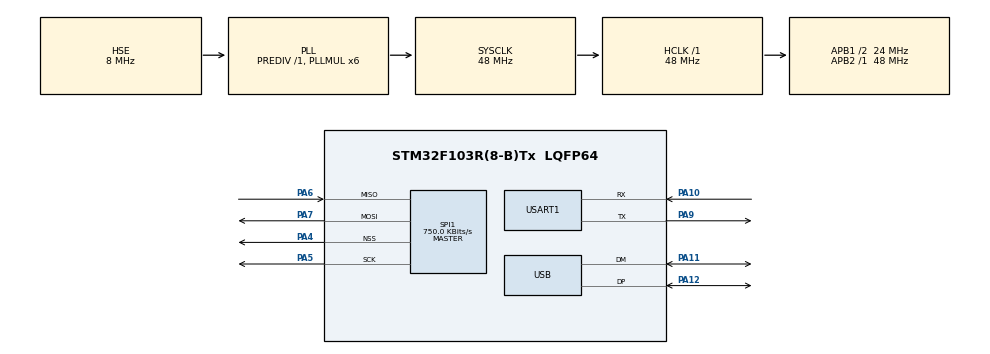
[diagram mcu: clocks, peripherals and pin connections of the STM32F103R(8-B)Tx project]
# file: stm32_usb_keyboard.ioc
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Mcu.Family=STM32F1
Mcu.Name=STM32F103R(8-B)Tx
Mcu.Package=LQFP64
NVIC.PriorityGroup=NVIC_PRIORITYGROUP_4
NVIC.USART1_IRQn=true\:0\:0\:false\:false\:true
NVIC.USB_LP_CAN1_RX0_IRQn=true\:0\:0\:false\:false\:true
PA10.Mode=Asynchronous
PA10.Signal=USART1_RX
PA11.Mode=Device
PA11.Signal=USB_DM
PA12.Mode=Device
PA12.Signal=USB_DP
PA4.Mode=NSS_Signal_Hard_Output
PA4.Signal=SPI1_NSS
PA5.Mode=Full_Duplex_Master
PA5.Signal=SPI1_SCK
PA6.Mode=Full_Duplex_Master
PA6.Signal=SPI1_MISO
PA7.Mode=Full_Duplex_Master
PA7.Signal=SPI1_MOSI
PA9.Mode=Asynchronous
PA9.Signal=USART1_TX
PC14-OSC32_IN.Mode=LSE-External-Oscillator
PC14-OSC32_IN.Signal=RCC_OSC32_IN
PC15-OSC32_OUT.Mode=LSE-External-Oscillator
PC15-OSC32_OUT.Signal=RCC_OSC32_OUT
PD0-OSC_IN.Mode=HSE-External-Oscillator
PD0-OSC_IN.Signal=RCC_OSC_IN
PD1-OSC_OUT.Mode=HSE-External-Oscillator
PD1-OSC_OUT.Signal=RCC_OSC_OUT
ProjectManager.HeapSize=0x200
ProjectManager.StackSize=0x400
ProjectManager.TargetToolchain=MDK-ARM V5
RCC.AHBFreq_Value=48000000
RCC.APB1CLKDivider=RCC_HCLK_DIV2
RCC.APB1Freq_Value=24000000
RCC.APB1TimFreq_Value=48000000
RCC.APB2Freq_Value=48000000
RCC.APB2TimFreq_Value=48000000
RCC.HCLKFreq_Value=48000000
RCC.HSIState=RCC_HSI_ON
RCC.PLLMUL=RCC_PLL_MUL6
RCC.SYSCLKFreq_VALUE=48000000
RCC.SYSCLKSource=RCC_SYSCLKSOURCE_PLLCLK
RCC.USBFreq_Value=48000000
SPI1.BaudRatePrescaler=SPI_BAUDRATEPRESCALER_64
SPI1.CalculateBaudRate=750.0 KBits/s
SPI1.Mode=SPI_MODE_MASTER
SPI1.VirtualNSS=VM_NSSHARD
USB_DEVICE.USBD_HandleTypeDef=hUsbDeviceFS
USB_DEVICE.VirtualMode=Hid
USB_DEVICE.VirtualModeFS=Hid_FS
VP_SYS_VS_ND.Mode=No_Debug
VP_USB_DEVICE_VS_USB_DEVICE_HID_FS.Mode=HID_FS
board=stm32_usb_keyboard

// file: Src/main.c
/**
  ******************************************************************************
  * File Name          : main.c
  * Description        : Main program body
  ******************************************************************************
  *
  * COPYRIGHT(c) 2018 STMicroelectronics
  *
  * Redistribution and use in source and binary forms, with or without modification,
  * are permitted provided that the following conditions are met:
  *   1. Redistributions of source code must retain the above copyright notice,
  *      this list of conditions and the following disclaimer.
  *   2. Redistributions in binary form must reproduce the above copyright notice,
  *      this list of conditions and the following disclaimer in the documentation
  *      and/or other materials provided with the distribution.
  *   3. Neither the name of STMicroelectronics nor the names of its contributors
  *      may be used to endorse or promote products derived from this software
  *      without specific prior written permission.
  *
  * THIS SOFTWARE IS PROVIDED BY THE COPYRIGHT HOLDERS AND CONTRIBUTORS "AS IS"
  * AND ANY EXPRESS OR IMPLIED WARRANTIES, INCLUDING, BUT NOT LIMITED TO, THE
  * IMPLIED WARRANTIES OF MERCHANTABILITY AND FITNESS FOR A PARTICULAR PURPOSE ARE
  * DISCLAIMED. IN NO EVENT SHALL THE COPYRIGHT HOLDER OR CONTRIBUTORS BE LIABLE
  * FOR ANY DIRECT, INDIRECT, INCIDENTAL, SPECIAL, EXEMPLARY, OR CONSEQUENTIAL
  * DAMAGES (INCLUDING, BUT NOT LIMITED TO, PROCUREMENT OF SUBSTITUTE GOODS OR
  * SERVICES; LOSS OF USE, DATA, OR PROFITS; OR BUSINESS INTERRUPTION) HOWEVER
  * CAUSED AND ON ANY THEORY OF LIABILITY, WHETHER IN CONTRACT, STRICT LIABILITY,
  * OR TORT (INCLUDING NEGLIGENCE OR OTHERWISE) ARISING IN ANY WAY OUT OF THE USE
  * OF THIS SOFTWARE, EVEN IF ADVISED OF THE POSSIBILITY OF SUCH DAMAGE.
  *
  ******************************************************************************
  */
#include "stm32f1xx_hal.h"
#include "usb_device.h"
#include "NRF24L01.h"

SPI_HandleTypeDef hspi1;

UART_HandleTypeDef huart1;

	uint8_t *nrf24L01tx_buf = NULL;
	uint8_t *nrf24L01rx_buf = NULL;
	uint8_t *rxdata = NULL;
/* USER CODE BEGIN PV */
/* Private variables ---------------------------------------------------------*/

/* USER CODE END PV */

void SystemClock_Config(void);
void Error_Handler(void);
static void MX_GPIO_Init(void);
static void MX_SPI1_Init(void);
static void MX_USART1_UART_Init(void);

/* USER CODE BEGIN PFP */
/* Private function prototypes -----------------------------------------------*/

/* USER CODE END PFP */

/* USER CODE BEGIN 0 */
extern USBD_HandleTypeDef hUsbDeviceFS;
/* USER CODE END 0 */

int main(void)
{

  /* USER CODE BEGIN 1 */
  uint8_t report[8];
	uint8_t i;
	uint8_t j;
	BYTE sta;

	uint8_t HID_Buffer[]={"Hello,HID!~"};
	nrf24L01tx_buf =  (uint8_t *)malloc(1*sizeof(uint8_t));
	*nrf24L01tx_buf = 0x0;
	nrf24L01rx_buf =  (uint8_t *)malloc(1*sizeof(uint8_t));
	*nrf24L01rx_buf = 0xff;
	rxdata = (uint8_t *)malloc(1*sizeof(uint8_t));
	*rxdata = 0x0;
	char buf[5];
	char count;
  /* USER CODE END 1 */

  /* MCU Configuration----------------------------------------------------------*/

  /* Reset of all peripherals, Initializes the Flash interface and the Systick. */
  HAL_Init();

  /* Configure the system clock */
  SystemClock_Config();

  /* Initialize all configured peripherals */
  MX_GPIO_Init();
  MX_SPI1_Init();
  MX_USB_DEVICE_Init();
  MX_USART1_UART_Init();
    NRF24L01B_Config();
  HAL_GPIO_WritePin(GPIOA, GPIO_PIN_3, GPIO_PIN_SET);
	SPI_RW_Reg(FLUSH_RX,0xff);
	SPI_RW_Reg(FLUSH_TX,0xff);

	HAL_NVIC_ClearPendingIRQ(EXTI1_IRQn);

	SetRX_Mode();
	HAL_GPIO_WritePin(GPIOA, GPIO_PIN_3, GPIO_PIN_SET);
	SPI_RW_Reg(NRF24L01_WRITEREG+STATUS,SPI_Read(STATUS));
  HAL_UART_Transmit(&huart1, HID_Buffer, 11, 10);
		for (i = 0;i < 0x7;i++)
		{
			report[i]	= 0;
		}
		report[2] = 0x53;
		for (i = 0;i < 0x7;i++)
		{

			report[i]	= 0;
		}
		SPI_Read_Buf(RX_ADDR_P0,buf,RX_ADR_WIDTH);

		for(count=0;count<RX_ADR_WIDTH;count++)
		{
				  HAL_UART_Transmit(&huart1,&buf[count], 1, 10);

		}
  /* Infinite loop */
  /* USER CODE BEGIN WHILE */
  while (1)
  {
		//report[0] = 0x01;
/*
		for(i = 0x58;i < 0x61;i++)
		{
			j = 0xff;
			while(j--);
			report[4] = i;
			USBD_HID_SendReport(&hUsbDeviceFS, report,8);
		}
*/

		if(*nrf24L01rx_buf != 0xff)
		{
			report[4] = *nrf24L01rx_buf;
			USBD_HID_SendReport(&hUsbDeviceFS, report,8);
			HID_Buffer[0] =  *nrf24L01rx_buf - 0x28;
			  HAL_UART_Transmit(&huart1, HID_Buffer, 11, 10);

			*nrf24L01rx_buf = 0xff;
		}
			sta=SPI_Read(STATUS);
			  HAL_UART_Transmit(&huart1, &sta, 1, 10);

  /* USER CODE END WHILE */

  }

}

/** System Clock Configuration
*/
void SystemClock_Config(void)
{

  RCC_OscInitTypeDef RCC_OscInitStruct;
  RCC_ClkInitTypeDef RCC_ClkInitStruct;
  RCC_PeriphCLKInitTypeDef PeriphClkInit;

  RCC_OscInitStruct.OscillatorType = RCC_OSCILLATORTYPE_HSE;
  RCC_OscInitStruct.HSEState = RCC_HSE_ON;
  RCC_OscInitStruct.HSEPredivValue = RCC_HSE_PREDIV_DIV1;
  RCC_OscInitStruct.PLL.PLLState = RCC_PLL_ON;
  RCC_OscInitStruct.PLL.PLLSource = RCC_PLLSOURCE_HSE;
  RCC_OscInitStruct.PLL.PLLMUL = RCC_PLL_MUL6;
  if (HAL_RCC_OscConfig(&RCC_OscInitStruct) != HAL_OK)
  {
    Error_Handler();
  }

  RCC_ClkInitStruct.ClockType = RCC_CLOCKTYPE_HCLK|RCC_CLOCKTYPE_SYSCLK
                              |RCC_CLOCKTYPE_PCLK1|RCC_CLOCKTYPE_PCLK2;
  RCC_ClkInitStruct.SYSCLKSource = RCC_SYSCLKSOURCE_PLLCLK;
  RCC_ClkInitStruct.AHBCLKDivider = RCC_SYSCLK_DIV1;
  RCC_ClkInitStruct.APB1CLKDivider = RCC_HCLK_DIV2;
  RCC_ClkInitStruct.APB2CLKDivider = RCC_HCLK_DIV1;
  if (HAL_RCC_ClockConfig(&RCC_ClkInitStruct, FLASH_LATENCY_1) != HAL_OK)
  {
    Error_Handler();
  }

  PeriphClkInit.PeriphClockSelection = RCC_PERIPHCLK_USB;
  PeriphClkInit.UsbClockSelection = RCC_USBCLKSOURCE_PLL;
  if (HAL_RCCEx_PeriphCLKConfig(&PeriphClkInit) != HAL_OK)
  {
    Error_Handler();
  }

  HAL_SYSTICK_Config(HAL_RCC_GetHCLKFreq()/1000);

  HAL_SYSTICK_CLKSourceConfig(SYSTICK_CLKSOURCE_HCLK);

  /* SysTick_IRQn interrupt configuration */
  HAL_NVIC_SetPriority(SysTick_IRQn, 0, 0);
}

/* SPI1 init function */
static void MX_SPI1_Init(void)
{

		GPIO_InitTypeDef GPIO_InitStruct;
  __HAL_RCC_GPIOA_CLK_ENABLE();

  __HAL_RCC_SPI1_CLK_ENABLE();

  /*Configure GPIO pin : PA1 */
  GPIO_InitStruct.Pin = GPIO_PIN_5|GPIO_PIN_7 ;
  GPIO_InitStruct.Mode = GPIO_MODE_AF_PP;
  GPIO_InitStruct.Pull = GPIO_PULLUP;
  HAL_GPIO_Init(GPIOA, &GPIO_InitStruct);

  GPIO_InitStruct.Pin = GPIO_PIN_6;
  GPIO_InitStruct.Mode = GPIO_MODE_AF_INPUT;
  GPIO_InitStruct.Pull = GPIO_NOPULL;
  HAL_GPIO_Init(GPIOA, &GPIO_InitStruct);

    GPIO_InitStruct.Pin = GPIO_PIN_4;
  GPIO_InitStruct.Mode = GPIO_MODE_OUTPUT_PP;
  GPIO_InitStruct.Pull = GPIO_PULLUP;
  HAL_GPIO_Init(GPIOA, &GPIO_InitStruct);

  hspi1.Instance = SPI1;
  hspi1.Init.Mode = SPI_MODE_MASTER;
  hspi1.Init.Direction = SPI_DIRECTION_2LINES;
  hspi1.Init.DataSize = SPI_DATASIZE_8BIT;
  hspi1.Init.CLKPolarity = SPI_POLARITY_LOW;
  hspi1.Init.CLKPhase = SPI_PHASE_1EDGE;
  hspi1.Init.NSS = SPI_NSS_SOFT;
  hspi1.Init.BaudRatePrescaler = SPI_BAUDRATEPRESCALER_128;
  hspi1.Init.FirstBit = SPI_FIRSTBIT_MSB;
  hspi1.Init.TIMode = SPI_TIMODE_DISABLE;
  hspi1.Init.CRCCalculation = SPI_CRCCALCULATION_DISABLE;
  hspi1.Init.CRCPolynomial = 10;
  if (HAL_SPI_Init(&hspi1) != HAL_OK)
  {
    Error_Handler();
  }

}

/* USART1 init function */
static void MX_USART1_UART_Init(void)
{

	GPIO_InitTypeDef GPIO_InitStruct;
	__HAL_RCC_USART1_CLK_ENABLE();

  GPIO_InitStruct.Pin = GPIO_PIN_9;
  GPIO_InitStruct.Mode = GPIO_MODE_AF_PP;
  GPIO_InitStruct.Pull = GPIO_PULLUP;
  GPIO_InitStruct.Speed = GPIO_SPEED_FREQ_HIGH;
  HAL_GPIO_Init(GPIOA, &GPIO_InitStruct);

    GPIO_InitStruct.Pin = GPIO_PIN_10;
  GPIO_InitStruct.Mode = GPIO_MODE_AF_INPUT;
  GPIO_InitStruct.Pull = GPIO_PULLUP;
  GPIO_InitStruct.Speed = GPIO_SPEED_FREQ_HIGH;
  HAL_GPIO_Init(GPIOA, &GPIO_InitStruct);

  huart1.Instance = USART1;
  huart1.Init.BaudRate = 115200;
  huart1.Init.WordLength = UART_WORDLENGTH_8B;
  huart1.Init.StopBits = UART_STOPBITS_1;
  huart1.Init.Parity = UART_PARITY_NONE;
  huart1.Init.Mode = UART_MODE_TX_RX;
  huart1.Init.HwFlowCtl = UART_HWCONTROL_NONE;
  huart1.Init.OverSampling = UART_OVERSAMPLING_16;
  if (HAL_UART_Init(&huart1) != HAL_OK)
  {
    Error_Handler();
  }

}

/** Configure pins as
        * Analog
        * Input
        * Output
        * EVENT_OUT
        * EXTI
*/
static void MX_GPIO_Init(void)
{

  /* GPIO Ports Clock Enable */

  GPIO_InitTypeDef GPIO_InitStruct;

  /* GPIO Ports Clock Enable */
  __HAL_RCC_GPIOC_CLK_ENABLE();
  __HAL_RCC_GPIOD_CLK_ENABLE();
  __HAL_RCC_GPIOA_CLK_ENABLE();
  __HAL_RCC_GPIOB_CLK_ENABLE();

  /*Configure GPIO pin : PA1 */
  GPIO_InitStruct.Pin = GPIO_PIN_1;
  GPIO_InitStruct.Mode = GPIO_MODE_IT_FALLING;
  GPIO_InitStruct.Pull = GPIO_NOPULL;
  HAL_GPIO_Init(GPIOA, &GPIO_InitStruct);

  HAL_NVIC_ClearPendingIRQ(EXTI1_IRQn);
	HAL_NVIC_SetPriority(EXTI1_IRQn, 1 ,0);
	HAL_NVIC_EnableIRQ(EXTI1_IRQn);

	GPIO_InitStruct.Pin = GPIO_PIN_3;
  GPIO_InitStruct.Mode = GPIO_MODE_OUTPUT_PP;
  GPIO_InitStruct.Pull = GPIO_PULLUP;
  HAL_GPIO_Init(GPIOA, &GPIO_InitStruct);
}

/* USER CODE BEGIN 4 */
/* USER CODE BEGIN 4 */
void EXTI1_IRQHandler(void)
{
	unsigned char sta,flag=0x01;
	uint8_t HID_Buffer[]={"intr"};

	HAL_NVIC_ClearPendingIRQ(EXTI1_IRQn);
	SetRX_Mode();
	HAL_GPIO_WritePin(GPIOA, GPIO_PIN_3, GPIO_PIN_SET);
	//USBD_CUSTOM_HID_SendReport(&hUsbDeviceFS, HID_Buffer,65);

	HAL_UART_Transmit(&huart1, HID_Buffer, 4, 10);

	//GPIO_WriteBit(GPIOA,GPIO_Pin_3,Bit_SET);
	sta = SPI_Read(STATUS);	// read register STATUS's value
	sta &= (RX_DR | TX_DS | MAX_RT);

		while(flag)
		{
			SPI_RW_Reg(NRF24L01_WRITEREG+STATUS,SPI_Read(STATUS));
			flag = SPI_Read(STATUS);	// read register STATUS's value
			flag &= (RX_DR | TX_DS | MAX_RT);
			}

	switch(sta)
		{
		case RX_DR:
				{

					SPI_Read_Buf(RD_RX_PLOAD,nrf24L01rx_buf,TX_PLOAD_WIDTH);
					SPI_RW_Reg(FLUSH_RX,0xff);
					//printf("\n receive data success \n");
					break;  // read receive payload from RX_FIFO buffer
			}

			default:
				{
						SPI_RW_Reg(FLUSH_RX,0xff);
						SPI_RW_Reg(FLUSH_TX,0xff);
						break;
					}

			}

		//GPIO_WriteBit(GPIOA,GPIO_Pin_3,Bit_RESET);

}
/* USER CODE END 4 */

void Error_Handler(void)
{
  while(1)
  {
  }
}

/************************ (C) COPYRIGHT STMicroelectronics *****END OF FILE****/
